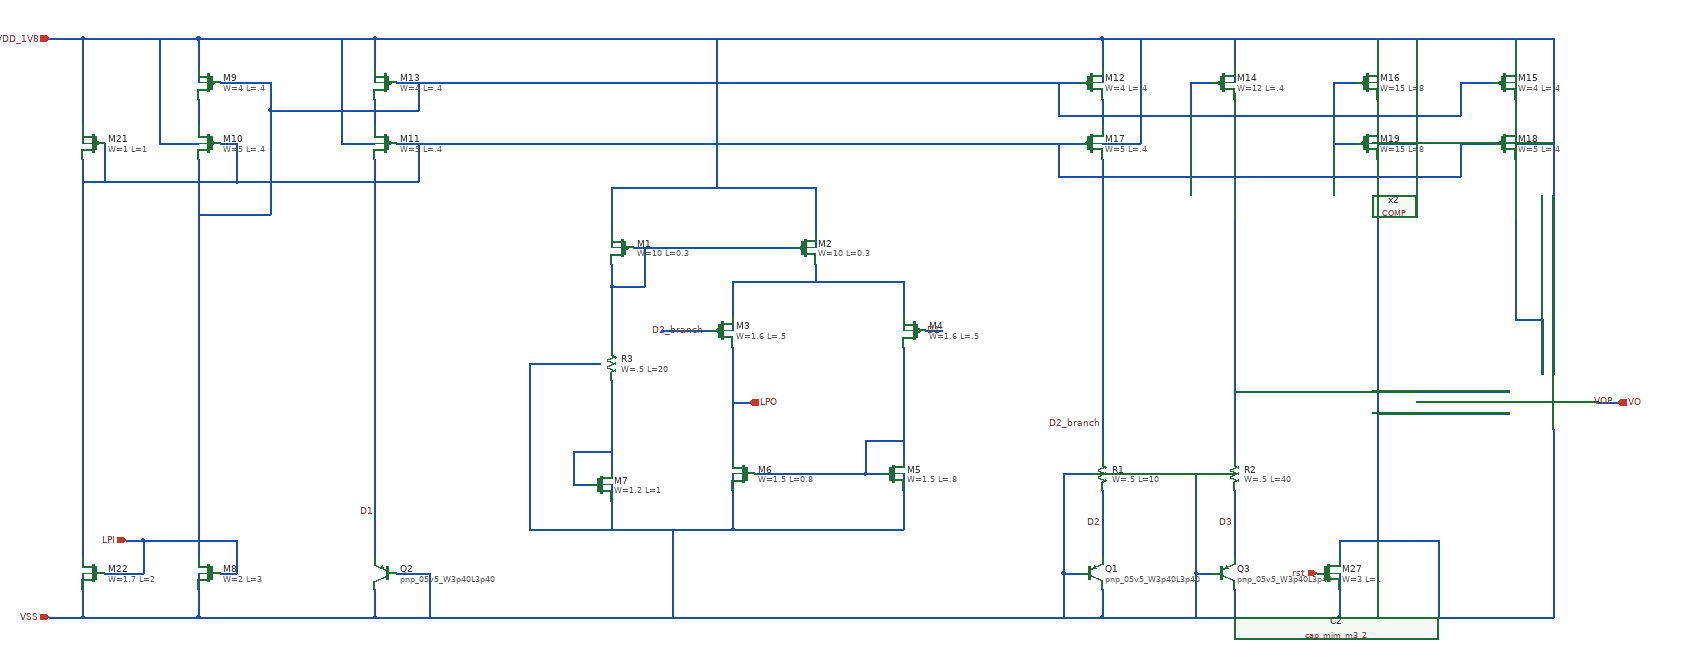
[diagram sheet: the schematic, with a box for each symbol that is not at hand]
v {xschem version=3.4.4 file_version=1.2
}
G {}
K {}
V {}
S {}
E {}
N 2300 -430 2300 -310 {
lab=D2}
N 980 -1250 980 -1200 {
lab=VDD_1V8}
N 2300 -1250 2300 -1200 {
lab=VDD_1V8}
N 2300 -1200 2300 -1170 {
lab=VDD_1V8}
N 980 -1200 980 -1170 {
lab=VDD_1V8}
N 980 -250 980 -200 {
lab=VSS}
N 2300 -250 2300 -200 {
lab=VSS}
N 2230 -280 2260 -280 {
lab=VSS}
N 2230 -280 2230 -200 {
lab=VSS}
N 1020 -280 1050 -280 {
lab=VSS}
N 2540 -430 2540 -310 {
lab=D3}
N 2470 -280 2500 -280 {
lab=VSS}
N 2300 -1250 2640 -1250 {
lab=VDD_1V8}
N 2540 -1200 2540 -1170 {
lab=VDD_1V8}
N 2540 -1040 2540 -510 {
lab=#net1}
N 2540 -510 2540 -490 {
lab=#net1}
N 2300 -200 2640 -200 {
lab=VSS}
N 2540 -250 2540 -200 {
lab=VSS}
N 2470 -280 2470 -200 {
lab=VSS}
N 2640 -1250 2910 -1250 {
lab=VDD_1V8}
N 2800 -1230 2800 -1200 {
lab=VDD_1V8}
N 2800 -1250 2800 -1230 {
lab=VDD_1V8}
N 1630 -810 1630 -750 {
lab=#net2}
N 1630 -810 1940 -810 {
lab=#net2}
N 1940 -810 1940 -750 {
lab=#net2}
N 1940 -690 1940 -490 {
lab=#net3}
N 1630 -690 1630 -490 {
lab=LPO}
N 1670 -460 1700 -460 {
lab=#net3}
N 1870 -460 1900 -460 {
lab=#net3}
N 1870 -520 1870 -460 {
lab=#net3}
N 1870 -520 1940 -520 {
lab=#net3}
N 1630 -430 1630 -360 {
lab=VSS}
N 1630 -360 1940 -360 {
lab=VSS}
N 1940 -430 1940 -360 {
lab=VSS}
N 1630 -460 1630 -430 {
lab=VSS}
N 1940 -460 1940 -430 {
lab=VSS}
N 1940 -750 1940 -720 {
lab=#net2}
N 1630 -750 1630 -720 {
lab=#net2}
N 1780 -900 1780 -870 {
lab=VDD_1V8}
N 1780 -840 1780 -810 {
lab=#net2}
N 1410 -900 1410 -870 {
lab=VDD_1V8}
N 1410 -840 1410 -800 {
lab=#net4}
N 1410 -800 1470 -800 {
lab=#net4}
N 1470 -870 1470 -800 {
lab=#net4}
N 1450 -870 1740 -870 {
lab=#net4}
N 1410 -980 1780 -980 {
lab=VDD_1V8}
N 1410 -800 1410 -740 {
lab=#net4}
N 1410 -740 1410 -730 {
lab=#net4}
N 1700 -460 1870 -460 {
lab=#net3}
N 1340 -440 1370 -440 {
lab=#net5}
N 1340 -500 1340 -440 {
lab=#net5}
N 1340 -500 1410 -500 {
lab=#net5}
N 1410 -440 1410 -410 {
lab=VSS}
N 1410 -630 1410 -470 {
lab=#net5}
N 1410 -410 1410 -360 {
lab=VSS}
N 1410 -730 1410 -690 {
lab=#net4}
N 1540 -720 1590 -720 {
lab=D2_branch}
N 700 -280 730 -280 {
lab=LPI}
N 730 -340 730 -280 {
lab=LPI}
N 660 -280 660 -250 {
lab=VSS}
N 660 -250 660 -200 {
lab=VSS}
N 660 -200 980 -200 {
lab=VSS}
N 660 -1250 660 -1200 {
lab=VDD_1V8}
N 660 -1200 660 -1170 {
lab=VDD_1V8}
N 660 -1140 660 -1090 {
lab=#net6}
N 730 -1060 730 -990 {
lab=#net7}
N 700 -1060 730 -1060 {
lab=#net7}
N 700 -1170 730 -1170 {
lab=#net8}
N 660 -1250 980 -1250 {
lab=VDD_1V8}
N 980 -1140 980 -1090 {
lab=#net9}
N 2300 -1140 2300 -1090 {
lab=#net10}
N 2540 -1150 2540 -1100 {
lab=#net1}
N 2540 -1250 2540 -1200 {
lab=VDD_1V8}
N 2220 -1170 2220 -1110 {
lab=#net8}
N 2220 -1110 2560 -1110 {
lab=#net8}
N 2460 -1170 2460 -1110 {
lab=#net8}
N 2460 -1170 2500 -1170 {
lab=#net8}
N 2300 -1030 2300 -490 {
lab=D2_branch}
N 1060 -1170 1060 -1120 {
lab=#net8}
N 1060 -1060 1060 -990 {
lab=#net7}
N 730 -1170 790 -1170 {
lab=#net8}
N 2560 -1110 2830 -1110 {
lab=#net8}
N 660 -1030 660 -860 {
lab=#net8}
N 660 -810 660 -310 {
lab=#net8}
N 1050 -280 1080 -280 {
lab=VSS}
N 1080 -220 1080 -200 {
lab=VSS}
N 1080 -280 1080 -230 {
lab=VSS}
N 1080 -230 1080 -220 {
lab=VSS}
N 980 -390 980 -310 {
lab=D1}
N 980 -550 980 -450 {
lab=D1}
N 980 -1030 980 -550 {
lab=D1}
N 980 -450 980 -390 {
lab=D1}
N 790 -1120 1060 -1120 {
lab=#net8}
N 1410 -980 1410 -900 {
lab=VDD_1V8}
N 1780 -980 1780 -900 {
lab=VDD_1V8}
N 660 -860 660 -810 {
lab=#net8}
N 450 -1090 450 -1060 {
lab=VDD_1V8}
N 450 -990 730 -990 {
lab=#net7}
N 450 -1250 450 -1090 {
lab=VDD_1V8}
N 450 -1250 660 -1250 {
lab=VDD_1V8}
N 450 -1030 450 -340 {
lab=#net7}
N 490 -1060 490 -990 {
lab=#net7}
N 730 -990 1060 -990 {
lab=#net7}
N 2540 -1100 2540 -1040 {
lab=#net1}
N 2480 -460 2520 -460 {
lab=VSS}
N 2470 -460 2470 -280 {
lab=VSS}
N 2470 -460 2480 -460 {
lab=VSS}
N 2230 -460 2230 -280 {
lab=VSS}
N 2230 -460 2280 -460 {
lab=VSS}
N 3050 -1230 3050 -1200 {
lab=VDD_1V8}
N 2220 -1060 2220 -1000 {
lab=#net7}
N 3050 -1250 3050 -1230 {
lab=VDD_1V8}
N 590 -1060 660 -1060 {
lab=VDD_1V8}
N 590 -1250 590 -1060 {
lab=VDD_1V8}
N 920 -1060 980 -1060 {
lab=VDD_1V8}
N 920 -1250 920 -1060 {
lab=VDD_1V8}
N 2300 -1060 2370 -1060 {
lab=VDD_1V8}
N 2370 -1250 2370 -1060 {
lab=VDD_1V8}
N 3120 -1250 3120 -1090 {
lab=VDD_1V8}
N 2850 -340 2910 -340 {
lab=VSS}
N 2730 -340 2730 -310 {
lab=VSS}
N 2730 -280 2730 -250 {
lab=VSS}
N 2730 -340 2770 -340 {
lab=VSS}
N 2910 -340 2910 -200 {
lab=VSS}
N 2810 -340 2840 -340 {
lab=VSS}
N 450 -340 450 -310 {
lab=#net7}
N 450 -250 450 -200 {
lab=VSS}
N 450 -280 450 -250 {
lab=VSS}
N 450 -200 660 -200 {
lab=VSS}
N 2720 -1170 2760 -1170 {
lab=#net8}
N 2720 -1170 2720 -1110 {
lab=#net8}
N 2760 -200 2840 -200 {
lab=VSS}
N 2800 -940 2800 -800 {
lab=VSS}
N 2800 -740 2800 -520 {
lab=VSS}
N 2640 -200 2730 -200 {
lab=VSS}
N 2730 -200 2760 -200 {
lab=VSS}
N 2840 -340 2850 -340 {
lab=VSS}
N 2830 -1110 2940 -1110 {
lab=#net8}
N 2910 -1250 3120 -1250 {
lab=VDD_1V8}
N 2770 -340 2810 -340 {
lab=VSS}
N 2840 -200 2880 -200 {
lab=VSS}
N 2730 -250 2730 -200 {
lab=VSS}
N 2900 -200 2950 -200 {
lab=VSS}
N 2880 -200 2900 -200 {
lab=VSS}
N 2800 -520 2800 -340 {
lab=VSS}
N 420 -1250 450 -1250 {
lab=VDD_1V8}
N 390 -200 420 -200 {
lab=VSS}
N 3120 -910 3120 -640 {
lab=VDD_1V8}
N 3120 -1090 3120 -910 {
lab=VDD_1V8}
N 2800 -570 3040 -570 {
lab=VSS}
N 2540 -610 3040 -610 {
lab=#net1}
N 3120 -540 3120 -200 {
lab=VSS}
N 2950 -200 3120 -200 {
lab=VSS}
N 3200 -590 3235 -590 {
lab=VO}
N 500 -280 530 -280 {
lab=LPI}
N 490 -280 500 -280 {
lab=LPI}
N 530 -280 560 -280 {
lab=LPI}
N 560 -340 560 -280 {
lab=LPI}
N 560 -340 730 -340 {
lab=LPI}
N 1630 -590 1660 -590 {
lab=LPO}
N 3050 -990 3050 -800 {
lab=#net11}
N 3050 -740 3100 -740 {
lab=#net12}
N 3100 -740 3100 -640 {
lab=#net12}
N 790 -1170 790 -1120 {
lab=#net8}
N 790 -1120 790 -930 {
lab=#net8}
N 660 -930 790 -930 {
lab=#net8}
N 1600 -1250 1600 -980 {
lab=VDD_1V8}
N 1520 -360 1520 -200 {
lab=VSS}
N 1300 -660 1390 -660 {
lab=VSS}
N 1300 -360 1630 -360 {
lab=VSS}
N 530 -340 560 -340 {
lab=LPI}
N 1500 -720 1540 -720 {
lab=D2_branch}
N 1980 -720 2010 -720 {
lab=D1}
N 980 -200 2300 -200 {
lab=VSS}
N 980 -1250 2300 -1250 {
lab=VDD_1V8}
N 1020 -1170 2260 -1170 {
lab=#net8}
N 1020 -1060 2260 -1060 {
lab=#net7}
N 2950 -1170 3010 -1170 {
lab=#net8}
N 2950 -1170 2950 -1110 {
lab=#net8}
N 2940 -1110 2950 -1110 {
lab=#net8}
N 3050 -1140 3050 -1090 {
lab=#net13}
N 3050 -1030 3050 -990 {
lab=#net11}
N 2950 -1060 3010 -1060 {
lab=#net7}
N 2950 -1060 2950 -1000 {
lab=#net7}
N 2220 -1000 2950 -1000 {
lab=#net7}
N 1260 -660 1300 -660 {
lab=VSS}
N 1260 -660 1260 -360 {
lab=VSS}
N 1260 -360 1300 -360 {
lab=VSS}
N 2800 -1140 2800 -1090 {
lab=#net14}
N 2720 -1060 2760 -1060 {
lab=#net7}
N 2720 -1060 2720 -1000 {
lab=#net7}
N 2800 -1030 2800 -940 {
lab=VSS}
N 2800 -1200 2800 -1170 {
lab=VDD_1V8}
N 2800 -1060 2870 -1060 {
lab=VDD_1V8}
N 2870 -1250 2870 -1060 {
lab=VDD_1V8}
N 3050 -1200 3050 -1170 {
lab=VDD_1V8}
N 3050 -1060 3120 -1060 {
lab=VDD_1V8}
N 420 -200 450 -200 {
lab=VSS}
N 390 -1250 420 -1250 {
lab=VDD_1V8}
N 2800 -800 2800 -740 {
lab=VSS}
N 3050 -800 3050 -740 {}
C {sky130_fd_pr/pnp_05v5.sym} 2280 -280 0 0 {name=Q1
model=pnp_05v5_W3p40L3p40
m=6
spiceprefix=X
}
C {sky130_fd_pr/pnp_05v5.sym} 1000 -280 0 1 {name=Q2
model=pnp_05v5_W3p40L3p40
m=1
spiceprefix=X
}
C {sky130_fd_pr/pfet_01v8.sym} 2280 -1170 0 0 {name=M12
L=.4
W=4
nf=2
mult=1
ad="'int((nf+1)/2) * W/nf * 0.29'" 
pd="'2*int((nf+1)/2) * (W/nf + 0.29)'"
as="'int((nf+2)/2) * W/nf * 0.29'" 
ps="'2*int((nf+2)/2) * (W/nf + 0.29)'"
nrd="'0.29 / W'" nrs="'0.29 / W'"
sa=0 sb=0 sd=0
model=pfet_01v8
spiceprefix=X
}
C {sky130_fd_pr/pfet_01v8.sym} 1000 -1170 0 1 {name=M13
L=.4
W=4
nf=2
mult=1
ad="'int((nf+1)/2) * W/nf * 0.29'" 
pd="'2*int((nf+1)/2) * (W/nf + 0.29)'"
as="'int((nf+2)/2) * W/nf * 0.29'" 
ps="'2*int((nf+2)/2) * (W/nf + 0.29)'"
nrd="'0.29 / W'" nrs="'0.29 / W'"
sa=0 sb=0 sd=0
model=pfet_01v8
spiceprefix=X
}
C {sky130_fd_pr/pfet_01v8.sym} 2520 -1170 0 0 {name=M14
L=.4
W=12
nf=2
mult=1
ad="'int((nf+1)/2) * W/nf * 0.29'" 
pd="'2*int((nf+1)/2) * (W/nf + 0.29)'"
as="'int((nf+2)/2) * W/nf * 0.29'" 
ps="'2*int((nf+2)/2) * (W/nf + 0.29)'"
nrd="'0.29 / W'" nrs="'0.29 / W'"
sa=0 sb=0 sd=0
model=pfet_01v8
spiceprefix=X
}
C {sky130_fd_pr/pnp_05v5.sym} 2520 -280 0 0 {name=Q3
model=pnp_05v5_W3p40L3p40
m=1
spiceprefix=X
}
C {devices/lab_wire.sym} 2300 -370 0 0 {name=p7 sig_type=std_logic lab=D2}
C {devices/lab_wire.sym} 2540 -370 0 0 {name=p8 sig_type=std_logic lab=D3}
C {sky130_fd_pr/pfet_01v8.sym} 2780 -1170 0 0 {name=M16
L=8
W=15
nf=2
mult=1
ad="'int((nf+1)/2) * W/nf * 0.29'" 
pd="'2*int((nf+1)/2) * (W/nf + 0.29)'"
as="'int((nf+2)/2) * W/nf * 0.29'" 
ps="'2*int((nf+2)/2) * (W/nf + 0.29)'"
nrd="'0.29 / W'" nrs="'0.29 / W'"
sa=0 sb=0 sd=0
model=pfet_01v8
spiceprefix=X
}
C {devices/lab_wire.sym} 980 -390 0 0 {name=p4 sig_type=std_logic lab=D1}
C {sky130_fd_pr/pfet_01v8.sym} 1430 -870 0 1 {name=M1
L=0.3
W=10
nf=2
mult=1
ad="'int((nf+1)/2) * W/nf * 0.29'" 
pd="'2*int((nf+1)/2) * (W/nf + 0.29)'"
as="'int((nf+2)/2) * W/nf * 0.29'" 
ps="'2*int((nf+2)/2) * (W/nf + 0.29)'"
nrd="'0.29 / W'" nrs="'0.29 / W'"
sa=0 sb=0 sd=0
model=pfet_01v8
spiceprefix=X
}
C {sky130_fd_pr/pfet_01v8.sym} 1760 -870 0 0 {name=M2
L=0.3
W=10
nf=2
mult=1
ad="'int((nf+1)/2) * W/nf * 0.29'" 
pd="'2*int((nf+1)/2) * (W/nf + 0.29)'"
as="'int((nf+2)/2) * W/nf * 0.29'" 
ps="'2*int((nf+2)/2) * (W/nf + 0.29)'"
nrd="'0.29 / W'" nrs="'0.29 / W'"
sa=0 sb=0 sd=0
model=pfet_01v8
spiceprefix=X
}
C {sky130_fd_pr/pfet_01v8.sym} 1610 -720 0 0 {name=M3
L=.5
W=1.6
nf=2
mult=1
ad="'int((nf+1)/2) * W/nf * 0.29'" 
pd="'2*int((nf+1)/2) * (W/nf + 0.29)'"
as="'int((nf+2)/2) * W/nf * 0.29'" 
ps="'2*int((nf+2)/2) * (W/nf + 0.29)'"
nrd="'0.29 / W'" nrs="'0.29 / W'"
sa=0 sb=0 sd=0
model=pfet_01v8
spiceprefix=X
}
C {sky130_fd_pr/pfet_01v8.sym} 1960 -720 0 1 {name=M4
L=.5
W=1.6
nf=2
mult=1
ad="'int((nf+1)/2) * W/nf * 0.29'" 
pd="'2*int((nf+1)/2) * (W/nf + 0.29)'"
as="'int((nf+2)/2) * W/nf * 0.29'" 
ps="'2*int((nf+2)/2) * (W/nf + 0.29)'"
nrd="'0.29 / W'" nrs="'0.29 / W'"
sa=0 sb=0 sd=0
model=pfet_01v8
spiceprefix=X
}
C {sky130_fd_pr/nfet_01v8.sym} 1920 -460 0 0 {name=M5
L=.8
W=1.5
nf=2 
mult=1
ad="'int((nf+1)/2) * W/nf * 0.29'" 
pd="'2*int((nf+1)/2) * (W/nf + 0.29)'"
as="'int((nf+2)/2) * W/nf * 0.29'" 
ps="'2*int((nf+2)/2) * (W/nf + 0.29)'"
nrd="'0.29 / W'" nrs="'0.29 / W'"
sa=0 sb=0 sd=0
model=nfet_01v8
spiceprefix=X
}
C {sky130_fd_pr/nfet_01v8.sym} 1650 -460 0 1 {name=M6
L=0.8
W=1.5
nf=2 
mult=1
ad="'int((nf+1)/2) * W/nf * 0.29'" 
pd="'2*int((nf+1)/2) * (W/nf + 0.29)'"
as="'int((nf+2)/2) * W/nf * 0.29'" 
ps="'2*int((nf+2)/2) * (W/nf + 0.29)'"
nrd="'0.29 / W'" nrs="'0.29 / W'"
sa=0 sb=0 sd=0
model=nfet_01v8
spiceprefix=X
}
C {devices/ipin.sym} 390 -1250 0 0 {name=p5 lab=VDD_1V8}
C {devices/ipin.sym} 390 -200 0 0 {name=p9 lab=VSS}
C {sky130_fd_pr/res_high_po.sym} 2540 -460 0 0 {name=R2
W=.5
L=40
model=res_high_po
spiceprefix=X
mult=1}
C {sky130_fd_pr/res_high_po.sym} 2300 -460 0 0 {name=R1
W=.5
L=10
model=res_high_po
spiceprefix=X
mult=1}
C {sky130_fd_pr/nfet_01v8.sym} 1390 -440 0 0 {name=M7
L=1
W=1.2
nf=2 
mult=1
ad="'int((nf+1)/2) * W/nf * 0.29'" 
pd="'2*int((nf+1)/2) * (W/nf + 0.29)'"
as="'int((nf+2)/2) * W/nf * 0.29'" 
ps="'2*int((nf+2)/2) * (W/nf + 0.29)'"
nrd="'0.29 / W'" nrs="'0.29 / W'"
sa=0 sb=0 sd=0
model=nfet_01v8
spiceprefix=X
}
C {sky130_fd_pr/res_high_po.sym} 1410 -660 0 0 {name=R3
W=.5
L=20
model=res_high_po
spiceprefix=X
mult=1}
C {devices/lab_wire.sym} 2010 -720 0 0 {name=p10 sig_type=std_logic lab=D1}
C {sky130_fd_pr/nfet_01v8.sym} 680 -280 0 1 {name=M8
L=3
W=2
nf=2 
mult=1
ad="'int((nf+1)/2) * W/nf * 0.29'" 
pd="'2*int((nf+1)/2) * (W/nf + 0.29)'"
as="'int((nf+2)/2) * W/nf * 0.29'" 
ps="'2*int((nf+2)/2) * (W/nf + 0.29)'"
nrd="'0.29 / W'" nrs="'0.29 / W'"
sa=0 sb=0 sd=0
model=nfet_01v8
spiceprefix=X
}
C {sky130_fd_pr/pfet_01v8.sym} 680 -1170 0 1 {name=M9
L=.4
W=4
nf=2
mult=1
ad="'int((nf+1)/2) * W/nf * 0.29'" 
pd="'2*int((nf+1)/2) * (W/nf + 0.29)'"
as="'int((nf+2)/2) * W/nf * 0.29'" 
ps="'2*int((nf+2)/2) * (W/nf + 0.29)'"
nrd="'0.29 / W'" nrs="'0.29 / W'"
sa=0 sb=0 sd=0
model=pfet_01v8
spiceprefix=X
}
C {sky130_fd_pr/pfet_01v8.sym} 680 -1060 0 1 {name=M10
L=.4
W=5
nf=2
mult=1
ad="'int((nf+1)/2) * W/nf * 0.29'" 
pd="'2*int((nf+1)/2) * (W/nf + 0.29)'"
as="'int((nf+2)/2) * W/nf * 0.29'" 
ps="'2*int((nf+2)/2) * (W/nf + 0.29)'"
nrd="'0.29 / W'" nrs="'0.29 / W'"
sa=0 sb=0 sd=0
model=pfet_01v8
spiceprefix=X
}
C {sky130_fd_pr/pfet_01v8.sym} 1000 -1060 0 1 {name=M11
L=.4
W=5
nf=2
mult=1
ad="'int((nf+1)/2) * W/nf * 0.29'" 
pd="'2*int((nf+1)/2) * (W/nf + 0.29)'"
as="'int((nf+2)/2) * W/nf * 0.29'" 
ps="'2*int((nf+2)/2) * (W/nf + 0.29)'"
nrd="'0.29 / W'" nrs="'0.29 / W'"
sa=0 sb=0 sd=0
model=pfet_01v8
spiceprefix=X
}
C {sky130_fd_pr/pfet_01v8.sym} 2280 -1060 0 0 {name=M17
L=.4
W=5
nf=2
mult=1
ad="'int((nf+1)/2) * W/nf * 0.29'" 
pd="'2*int((nf+1)/2) * (W/nf + 0.29)'"
as="'int((nf+2)/2) * W/nf * 0.29'" 
ps="'2*int((nf+2)/2) * (W/nf + 0.29)'"
nrd="'0.29 / W'" nrs="'0.29 / W'"
sa=0 sb=0 sd=0
model=pfet_01v8
spiceprefix=X
}
C {sky130_fd_pr/pfet_01v8.sym} 470 -1060 0 1 {name=M21
L=1
W=1
nf=2
mult=1
ad="'int((nf+1)/2) * W/nf * 0.29'" 
pd="'2*int((nf+1)/2) * (W/nf + 0.29)'"
as="'int((nf+2)/2) * W/nf * 0.29'" 
ps="'2*int((nf+2)/2) * (W/nf + 0.29)'"
nrd="'0.29 / W'" nrs="'0.29 / W'"
sa=0 sb=0 sd=0
model=pfet_01v8
spiceprefix=X
}
C {sky130_fd_pr/nfet_01v8.sym} 470 -280 0 1 {name=M22
L=2
W=1.7
nf=2 
mult=1
ad="'int((nf+1)/2) * W/nf * 0.29'" 
pd="'2*int((nf+1)/2) * (W/nf + 0.29)'"
as="'int((nf+2)/2) * W/nf * 0.29'" 
ps="'2*int((nf+2)/2) * (W/nf + 0.29)'"
nrd="'0.29 / W'" nrs="'0.29 / W'"
sa=0 sb=0 sd=0
model=nfet_01v8
spiceprefix=X
}
C {devices/ipin.sym} 2690 -280 0 0 {name=p20 lab=rst}
C {sky130_fd_pr/nfet_01v8.sym} 2710 -280 0 0 {name=M27
L=1
W=3
nf=2 
mult=1
ad="'int((nf+1)/2) * W/nf * 0.29'" 
pd="'2*int((nf+1)/2) * (W/nf + 0.29)'"
as="'int((nf+2)/2) * W/nf * 0.29'" 
ps="'2*int((nf+2)/2) * (W/nf + 0.29)'"
nrd="'0.29 / W'" nrs="'0.29 / W'"
sa=0 sb=0 sd=0
model=nfet_01v8
spiceprefix=X
}
C {CNR_GR02_SKY130NM/COMP.sym} 3000 -690 0 0 {name=x2}
C {sky130_fd_pr/pfet_01v8.sym} 3030 -1170 0 0 {name=M15
L=.4
W=4
nf=2
mult=1
ad="'int((nf+1)/2) * W/nf * 0.29'" 
pd="'2*int((nf+1)/2) * (W/nf + 0.29)'"
as="'int((nf+2)/2) * W/nf * 0.29'" 
ps="'2*int((nf+2)/2) * (W/nf + 0.29)'"
nrd="'0.29 / W'" nrs="'0.29 / W'"
sa=0 sb=0 sd=0
model=pfet_01v8
spiceprefix=X
}
C {sky130_fd_pr/pfet_01v8.sym} 3030 -1060 0 0 {name=M18
L=.4
W=5
nf=2
mult=1
ad="'int((nf+1)/2) * W/nf * 0.29'" 
pd="'2*int((nf+1)/2) * (W/nf + 0.29)'"
as="'int((nf+2)/2) * W/nf * 0.29'" 
ps="'2*int((nf+2)/2) * (W/nf + 0.29)'"
nrd="'0.29 / W'" nrs="'0.29 / W'"
sa=0 sb=0 sd=0
model=pfet_01v8
spiceprefix=X
}
C {sky130_fd_pr/cap_mim_m3_2.sym} 2910 -290 0 1 {name=C2 model=cap_mim_m3_2 W=80 L=80 MF=1 spiceprefix=X}
C {devices/opin.sym} 1660 -590 0 0 {name=p2 lab=LPO}
C {devices/ipin.sym} 530 -340 0 0 {name=p11 lab=LPI}
C {devices/opin.sym} 3235 -590 0 0 {name=p6 lab=VO}
C {devices/lab_wire.sym} 1580 -720 0 0 {name=p1 sig_type=std_logic lab=D2_branch}
C {devices/lab_wire.sym} 2300 -550 0 0 {name=p3 sig_type=std_logic lab=D2_branch}
C {sky130_fd_pr/pfet_01v8.sym} 2780 -1060 0 0 {name=M19
L=8
W=15
nf=2
mult=1
ad="'int((nf+1)/2) * W/nf * 0.29'" 
pd="'2*int((nf+1)/2) * (W/nf + 0.29)'"
as="'int((nf+2)/2) * W/nf * 0.29'" 
ps="'2*int((nf+2)/2) * (W/nf + 0.29)'"
nrd="'0.29 / W'" nrs="'0.29 / W'"
sa=0 sb=0 sd=0
model=pfet_01v8
spiceprefix=X
}
C {devices/lab_wire.sym} 3230 -590 0 0 {name=p15 sig_type=std_logic lab=VOP}
